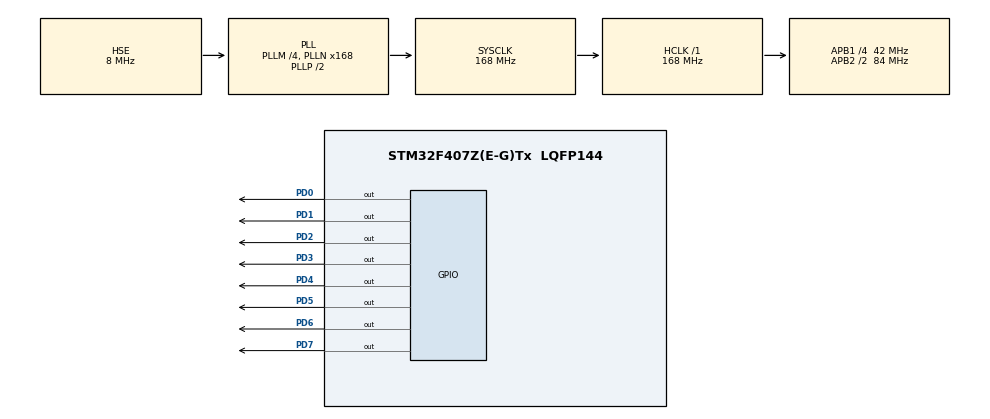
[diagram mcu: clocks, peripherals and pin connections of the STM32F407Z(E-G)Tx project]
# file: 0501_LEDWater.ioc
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Mcu.Family=STM32F4
Mcu.Name=STM32F407Z(E-G)Tx
Mcu.Package=LQFP144
NVIC.PriorityGroup=NVIC_PRIORITYGROUP_4
PA13.Mode=Serial_Wire
PA13.Signal=SYS_JTMS-SWDIO
PA14.Mode=Serial_Wire
PA14.Signal=SYS_JTCK-SWCLK
PD0.PinState=GPIO_PIN_RESET
PD0.Signal=GPIO_Output
PD1.PinState=GPIO_PIN_RESET
PD1.Signal=GPIO_Output
PD2.PinState=GPIO_PIN_RESET
PD2.Signal=GPIO_Output
PD3.PinState=GPIO_PIN_RESET
PD3.Signal=GPIO_Output
PD4.PinState=GPIO_PIN_RESET
PD4.Signal=GPIO_Output
PD5.PinState=GPIO_PIN_RESET
PD5.Signal=GPIO_Output
PD6.PinState=GPIO_PIN_RESET
PD6.Signal=GPIO_Output
PD7.GPIO_ModeDefaultOutputPP=GPIO_MODE_OUTPUT_PP
PD7.GPIO_PuPd=GPIO_NOPULL
PD7.PinState=GPIO_PIN_RESET
PD7.Signal=GPIO_Output
PH0-OSC_IN.Mode=HSE-External-Oscillator
PH0-OSC_IN.Signal=RCC_OSC_IN
PH1-OSC_OUT.Mode=HSE-External-Oscillator
PH1-OSC_OUT.Signal=RCC_OSC_OUT
ProjectManager.HeapSize=0x200
ProjectManager.StackSize=0x400
ProjectManager.TargetToolchain=STM32CubeIDE
RCC.48MHZClocksFreq_Value=84000000
RCC.AHBFreq_Value=168000000
RCC.APB1CLKDivider=RCC_HCLK_DIV4
RCC.APB1Freq_Value=42000000
RCC.APB1TimFreq_Value=84000000
RCC.APB2CLKDivider=RCC_HCLK_DIV2
RCC.APB2Freq_Value=84000000
RCC.APB2TimFreq_Value=168000000
RCC.CortexFreq_Value=168000000
RCC.HCLKFreq_Value=168000000
RCC.HSE_VALUE=8000000
RCC.HSI_VALUE=16000000
RCC.LSE_VALUE=32768
RCC.PLLM=4
RCC.PLLN=168
RCC.PLLSourceVirtual=RCC_PLLSOURCE_HSE
RCC.SYSCLKFreq_VALUE=168000000
RCC.SYSCLKSource=RCC_SYSCLKSOURCE_PLLCLK
RCC.VCOOutputFreq_Value=336000000
board=custom

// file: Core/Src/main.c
/* USER CODE BEGIN Header */
/**
  ******************************************************************************
  * @file           : main.c
  * @brief          : Main program body
  ******************************************************************************
  * @attention
  *
  * Copyright (c) 2026 STMicroelectronics.
  * All rights reserved.
  *
  * This software is licensed under terms that can be found in the LICENSE file
  * in the root directory of this software component.
  * If no LICENSE file comes with this software, it is provided AS-IS.
  *
  ******************************************************************************
  */
/* USER CODE END Header */
#include "main.h"

/* USER CODE BEGIN PV */
uint8_t i;
uint16_t led_mask = 0x0001;
/* USER CODE END PV */

void SystemClock_Config(void);
static void MX_GPIO_Init(void);

int main(void)
{

  /* MCU Configuration--------------------------------------------------------*/

  /* Reset of all peripherals, Initializes the Flash interface and the Systick. */
  HAL_Init();

  /* Configure the system clock */
  SystemClock_Config();

  /* Initialize all configured peripherals */
  MX_GPIO_Init();

  /* Infinite loop */
  while (1)
  {

    /* USER CODE BEGIN 3 */
    for(i = 0; i < 8; i++)
    {
        // 全部熄灭 PF0~PF7置高
        HAL_GPIO_WritePin(GPIOF, GPIO_PIN_0|GPIO_PIN_1|GPIO_PIN_2|GPIO_PIN_3|GPIO_PIN_4|GPIO_PIN_5|GPIO_PIN_6|GPIO_PIN_7, GPIO_PIN_SET);
        // 点亮当前LED
        HAL_GPIO_WritePin(GPIOF, led_mask, GPIO_PIN_RESET);
        HAL_Delay(400);
        led_mask = led_mask << 1;
    }
    led_mask = 0x0001; // 回到第一个灯L1
    /* USER CODE END 3 */
  }
}

void SystemClock_Config(void)
{
  RCC_OscInitTypeDef RCC_OscInitStruct = {0};
  RCC_ClkInitTypeDef RCC_ClkInitStruct = {0};

  /** Configure the main internal regulator output voltage
  */
  __HAL_RCC_PWR_CLK_ENABLE();
  __HAL_PWR_VOLTAGESCALING_CONFIG(PWR_REGULATOR_VOLTAGE_SCALE1);

  /** Initializes the RCC Oscillators according to the specified parameters
  * in the RCC_OscInitTypeDef structure.
  */
  RCC_OscInitStruct.OscillatorType = RCC_OSCILLATORTYPE_HSE;
  RCC_OscInitStruct.HSEState = RCC_HSE_ON;
  RCC_OscInitStruct.PLL.PLLState = RCC_PLL_ON;
  RCC_OscInitStruct.PLL.PLLSource = RCC_PLLSOURCE_HSE;
  RCC_OscInitStruct.PLL.PLLM = 4;
  RCC_OscInitStruct.PLL.PLLN = 168;
  RCC_OscInitStruct.PLL.PLLP = RCC_PLLP_DIV2;
  RCC_OscInitStruct.PLL.PLLQ = 4;
  if (HAL_RCC_OscConfig(&RCC_OscInitStruct) != HAL_OK)
  {
    Error_Handler();
  }

  /** Initializes the CPU, AHB and APB buses clocks
  */
  RCC_ClkInitStruct.ClockType = RCC_CLOCKTYPE_HCLK|RCC_CLOCKTYPE_SYSCLK
                              |RCC_CLOCKTYPE_PCLK1|RCC_CLOCKTYPE_PCLK2;
  RCC_ClkInitStruct.SYSCLKSource = RCC_SYSCLKSOURCE_PLLCLK;
  RCC_ClkInitStruct.AHBCLKDivider = RCC_SYSCLK_DIV1;
  RCC_ClkInitStruct.APB1CLKDivider = RCC_HCLK_DIV4;
  RCC_ClkInitStruct.APB2CLKDivider = RCC_HCLK_DIV2;

  if (HAL_RCC_ClockConfig(&RCC_ClkInitStruct, FLASH_LATENCY_5) != HAL_OK)
  {
    Error_Handler();
  }
}

static void MX_GPIO_Init(void)
{
  GPIO_InitTypeDef GPIO_InitStruct = {0};

  /* GPIO Ports Clock Enable */
  __HAL_RCC_GPIOF_CLK_ENABLE();
  __HAL_RCC_GPIOH_CLK_ENABLE();
  __HAL_RCC_GPIOA_CLK_ENABLE();

  /*Configure GPIO pin Output Level */
  HAL_GPIO_WritePin(GPIOF, GPIO_PIN_0|GPIO_PIN_1|GPIO_PIN_2|GPIO_PIN_3
                          |GPIO_PIN_4|GPIO_PIN_5|GPIO_PIN_6|GPIO_PIN_7, GPIO_PIN_SET);

  /*Configure GPIO pins : PF0 PF1 PF2 PF3
                           PF4 PF5 PF6 PF7 */
  GPIO_InitStruct.Pin = GPIO_PIN_0|GPIO_PIN_1|GPIO_PIN_2|GPIO_PIN_3
                          |GPIO_PIN_4|GPIO_PIN_5|GPIO_PIN_6|GPIO_PIN_7;
  GPIO_InitStruct.Mode = GPIO_MODE_OUTPUT_PP;
  GPIO_InitStruct.Pull = GPIO_NOPULL;
  GPIO_InitStruct.Speed = GPIO_SPEED_FREQ_LOW;
  HAL_GPIO_Init(GPIOF, &GPIO_InitStruct);

}

void Error_Handler(void)
{
  __disable_irq();
  while (1)
  {
  }
}
